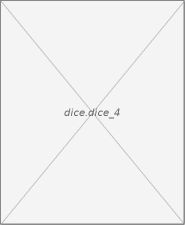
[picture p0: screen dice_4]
VISUALIZATION dice_4  // 185x225
VAR_IN_OUT
VAR_IN_OUT
	
END_VAR
    Image (0,0 185x225), image: dice.dice_4
END_VISUALIZATION
